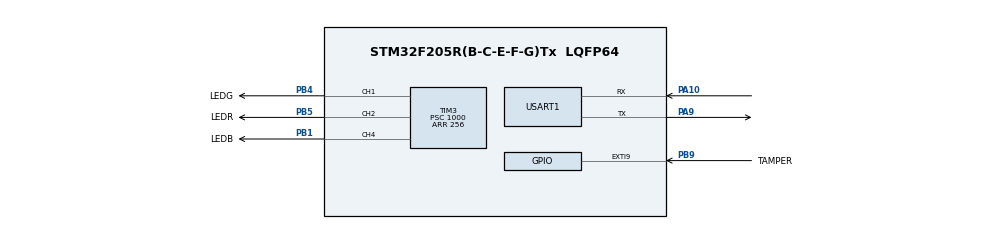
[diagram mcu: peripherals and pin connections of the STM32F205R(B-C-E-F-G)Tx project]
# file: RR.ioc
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Dma.Request0=USART1_RX
Dma.Request1=USART1_TX
Dma.USART1_RX.0.Direction=DMA_PERIPH_TO_MEMORY
Dma.USART1_RX.0.FIFOMode=DMA_FIFOMODE_DISABLE
Dma.USART1_RX.0.Instance=DMA2_Stream2
Dma.USART1_RX.0.MemDataAlignment=DMA_MDATAALIGN_BYTE
Dma.USART1_RX.0.MemInc=DMA_MINC_ENABLE
Dma.USART1_RX.0.Mode=DMA_NORMAL
Dma.USART1_RX.0.PeriphDataAlignment=DMA_PDATAALIGN_BYTE
Dma.USART1_RX.0.PeriphInc=DMA_PINC_DISABLE
Dma.USART1_RX.0.Priority=DMA_PRIORITY_LOW
Dma.USART1_TX.1.Direction=DMA_MEMORY_TO_PERIPH
Dma.USART1_TX.1.FIFOMode=DMA_FIFOMODE_DISABLE
Dma.USART1_TX.1.Instance=DMA2_Stream7
Dma.USART1_TX.1.MemDataAlignment=DMA_MDATAALIGN_BYTE
Dma.USART1_TX.1.MemInc=DMA_MINC_ENABLE
Dma.USART1_TX.1.Mode=DMA_NORMAL
Dma.USART1_TX.1.PeriphDataAlignment=DMA_PDATAALIGN_BYTE
Dma.USART1_TX.1.PeriphInc=DMA_PINC_DISABLE
Dma.USART1_TX.1.Priority=DMA_PRIORITY_LOW
Mcu.Family=STM32F2
Mcu.Name=STM32F205R(B-C-E-F-G)Tx
Mcu.Package=LQFP64
NVIC.DMA2_Stream2_IRQn=true\:0\:0\:false\:false\:true\:false\:true
NVIC.DMA2_Stream7_IRQn=true\:0\:0\:false\:false\:true\:false\:true
NVIC.EXTI9_5_IRQn=true\:0\:0\:false\:false\:true\:true\:true
NVIC.PriorityGroup=NVIC_PRIORITYGROUP_4
NVIC.USART1_IRQn=true\:0\:0\:false\:false\:true\:true\:true
PA10.Mode=Asynchronous
PA10.Signal=USART1_RX
PA9.Mode=Asynchronous
PA9.Signal=USART1_TX
PB1.GPIO_Label=LEDB
PB1.Signal=S_TIM3_CH4
PB4.GPIO_Label=LEDG
PB4.Signal=S_TIM3_CH1
PB5.GPIO_Label=LEDR
PB5.Signal=S_TIM3_CH2
PB9.GPIO_Label=TAMPER
PB9.GPIO_PuPd=GPIO_PULLUP
PB9.Signal=GPXTI9
PH0-OSC_IN.Mode=HSE-External-Oscillator
PH0-OSC_IN.Signal=RCC_OSC_IN
PH1-OSC_OUT.Mode=HSE-External-Oscillator
PH1-OSC_OUT.Signal=RCC_OSC_OUT
ProjectManager.HeapSize=0x200
ProjectManager.StackSize=0x400
ProjectManager.TargetToolchain=Makefile
RCC.48MHZClocksFreq_Value=56000000
RCC.AHBFreq_Value=112000000
RCC.APB1CLKDivider=RCC_HCLK_DIV4
RCC.APB1Freq_Value=28000000
RCC.APB1TimFreq_Value=56000000
RCC.APB2CLKDivider=RCC_HCLK_DIV2
RCC.APB2Freq_Value=56000000
RCC.APB2TimFreq_Value=112000000
RCC.CortexFreq_Value=112000000
RCC.HCLKFreq_Value=112000000
RCC.HSE_VALUE=8000000
RCC.HSI_VALUE=16000000
RCC.LSE_VALUE=32768
RCC.PLLM=8
RCC.PLLN=224
RCC.PLLSourceVirtual=RCC_PLLSOURCE_HSE
RCC.SYSCLKFreq_VALUE=112000000
RCC.SYSCLKSource=RCC_SYSCLKSOURCE_PLLCLK
RCC.VCOOutputFreq_Value=224000000
SH.S_TIM3_CH1.0=TIM3_CH1,PWM Generation1 CH1
SH.S_TIM3_CH2.0=TIM3_CH2,PWM Generation2 CH2
SH.S_TIM3_CH4.0=TIM3_CH4,PWM Generation4 CH4
TIM3.Channel-PWM\ Generation1\ CH1=TIM_CHANNEL_1
TIM3.Channel-PWM\ Generation2\ CH2=TIM_CHANNEL_2
TIM3.Channel-PWM\ Generation4\ CH4=TIM_CHANNEL_4
TIM3.ClockDivision=TIM_CLOCKDIVISION_DIV2
TIM3.Period=256
TIM3.Prescaler=1000
TIM3.Pulse-PWM\ Generation1\ CH1=0
TIM3.Pulse-PWM\ Generation4\ CH4=0
USART1.VirtualMode=VM_ASYNC
VP_TIM3_VS_ClockSourceINT.Mode=Internal
board=custom

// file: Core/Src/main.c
/* USER CODE BEGIN Header */
/**
  ******************************************************************************
  * @file           : main.c
  * @brief          : Main program body
  ******************************************************************************
  * @attention
  *
  * Copyright (c) 2024 STMicroelectronics.
  * All rights reserved.
  *
  * This software is licensed under terms that can be found in the LICENSE file
  * in the root directory of this software component.
  * If no LICENSE file comes with this software, it is provided AS-IS.
  *
  ******************************************************************************
  */
/* USER CODE END Header */
#include "main.h"

/* USER CODE BEGIN Includes */

#include<string.h>
#include<command_line.h>
#include<motor.h>

/* USER CODE END Includes */

TIM_HandleTypeDef htim3;

UART_HandleTypeDef huart1;
DMA_HandleTypeDef hdma_usart1_rx;
DMA_HandleTypeDef hdma_usart1_tx;

void SystemClock_Config(void);
static void MX_GPIO_Init(void);
static void MX_DMA_Init(void);
static void MX_TIM3_Init(void);
static void MX_USART1_UART_Init(void);

/* USER CODE BEGIN 0 */

char *user_data = "The application is running\r\n"; //demo data for transmission-
char *command;
uint8_t data_buffer[100]; // data buffer
uint8_t recvd_data; // receive buffer
uint32_t count=0; // count how many bytes are received
uint8_t command_flag = 0;

/* USER CODE END 0 */

int main(void)
{

  /* MCU Configuration--------------------------------------------------------*/

  /* Reset of all peripherals, Initializes the Flash interface and the Systick. */
  HAL_Init();

  /* Configure the system clock */
  SystemClock_Config();

  /* Initialize all configured peripherals */
  MX_GPIO_Init();
  MX_DMA_Init();
  MX_TIM3_Init();
  MX_USART1_UART_Init();
  /* USER CODE BEGIN 2 */

  			HAL_GPIO_WritePin(GPIOC, GPIO_FL_Pin, GPIO_PIN_RESET);
				HAL_GPIO_WritePin(GPIOC, GPIO_FR_Pin, GPIO_PIN_RESET);
				HAL_GPIO_WritePin(GPIOC, GPIO_BL_Pin, GPIO_PIN_RESET);
				HAL_GPIO_WritePin(GPIOC, GPIO_BR_Pin, GPIO_PIN_RESET);

  HAL_UART_Transmit_IT(&huart1,(uint8_t*)user_data,strlen(user_data)); //Transmit data in interrupt mode
  HAL_UART_Receive_IT(&huart1,&recvd_data,1); //receive data from data buffer interrupt mode

  /* USER CODE END 2 */

  /* Infinite loop */
  while (1)
  {

    /* USER CODE BEGIN 3 */

    if(command_flag){
      Get_Command(data_buffer);
    }

    if (GPIO_PIN_SET == HAL_GPIO_ReadPin(GPIOA, GPIO_PIN_0)) {

		  HAL_GPIO_WritePin(GPIOC, GPIO_PIN_13, GPIO_PIN_SET);

      TIM3 -> CCR1 = 1000;
      TIM3 -> CCR2 = 1000;
      TIM3 -> CCR3 = 1000;
      TIM3 -> CCR4 = 1000;

      HAL_TIM_PWM_Stop(&htim3, TIM_CHANNEL_1);
		  HAL_TIM_PWM_Stop(&htim3, TIM_CHANNEL_2);
		  HAL_TIM_PWM_Stop(&htim3, TIM_CHANNEL_3);
		  HAL_TIM_PWM_Stop(&htim3, TIM_CHANNEL_4);

    } else {

		  HAL_GPIO_WritePin(GPIOC, GPIO_PIN_13, GPIO_PIN_RESET);

		  HAL_Delay(2000);

		  HAL_TIM_PWM_Start(&htim3, TIM_CHANNEL_1);
		  HAL_TIM_PWM_Start(&htim3, TIM_CHANNEL_2);
		  HAL_TIM_PWM_Start(&htim3, TIM_CHANNEL_3);
		  HAL_TIM_PWM_Start(&htim3, TIM_CHANNEL_4);

      /*
		  wheelControl(frontright, 8);
		  HAL_Delay(1000);

		  wheelControl(frontright, 0);
		  HAL_Delay(1000);

		  wheelControl(backright, 8);
		  HAL_Delay(1000);

		  wheelControl(backright, 0);
		  HAL_Delay(1000);

		  wheelControl(frontleft, 8);
		  HAL_Delay(1000);

		  wheelControl(frontleft, 0);
		  HAL_Delay(1000);

		  wheelControl(backleft, 8);
		  HAL_Delay(1000);

		  wheelControl(backleft, 0);
		  HAL_Delay(1000);
*/

		  //wheelControl(backleft, 20);
//	  TIM3 -> CCR1 = 1000;
//	  TIM4 -> CCR1 = 199;

    TIM1 -> CCR2 = 1000;
    TIM2 -> CCR2 = 0;

 //   TIM1 -> CCR3 = 1000;
//    TIM2 -> CCR3 = 199;

//    TIM1 -> CCR4 = 1000;
//    TIM2 -> CCR4 = 199;

	  HAL_Delay(4000);

    }
  }
  /* USER CODE END 3 */
}

void SystemClock_Config(void)
{
  RCC_OscInitTypeDef RCC_OscInitStruct = {0};
  RCC_ClkInitTypeDef RCC_ClkInitStruct = {0};

  /** Configure the main internal regulator output voltage
  */
  __HAL_RCC_PWR_CLK_ENABLE();
  __HAL_PWR_VOLTAGESCALING_CONFIG(PWR_REGULATOR_VOLTAGE_SCALE2);

  /** Initializes the RCC Oscillators according to the specified parameters
  * in the RCC_OscInitTypeDef structure.
  */
  RCC_OscInitStruct.OscillatorType = RCC_OSCILLATORTYPE_HSE;
  RCC_OscInitStruct.HSEState = RCC_HSE_ON;
  RCC_OscInitStruct.PLL.PLLState = RCC_PLL_ON;
  RCC_OscInitStruct.PLL.PLLSource = RCC_PLLSOURCE_HSE;
  RCC_OscInitStruct.PLL.PLLM = 25;
  RCC_OscInitStruct.PLL.PLLN = 168;
  RCC_OscInitStruct.PLL.PLLP = RCC_PLLP_DIV2;
  RCC_OscInitStruct.PLL.PLLQ = 4;
  if (HAL_RCC_OscConfig(&RCC_OscInitStruct) != HAL_OK)
  {
    Error_Handler();
  }

  /** Initializes the CPU, AHB and APB buses clocks
  */
  RCC_ClkInitStruct.ClockType = RCC_CLOCKTYPE_HCLK|RCC_CLOCKTYPE_SYSCLK
                              |RCC_CLOCKTYPE_PCLK1|RCC_CLOCKTYPE_PCLK2;
  RCC_ClkInitStruct.SYSCLKSource = RCC_SYSCLKSOURCE_PLLCLK;
  RCC_ClkInitStruct.AHBCLKDivider = RCC_SYSCLK_DIV1;
  RCC_ClkInitStruct.APB1CLKDivider = RCC_HCLK_DIV2;
  RCC_ClkInitStruct.APB2CLKDivider = RCC_HCLK_DIV1;

  if (HAL_RCC_ClockConfig(&RCC_ClkInitStruct, FLASH_LATENCY_2) != HAL_OK)
  {
    Error_Handler();
  }
}

static void MX_TIM3_Init(void)
{

  TIM_ClockConfigTypeDef sClockSourceConfig = {0};
  TIM_MasterConfigTypeDef sMasterConfig = {0};
  TIM_OC_InitTypeDef sConfigOC = {0};

  htim3.Instance = TIM3;
  htim3.Init.Prescaler = 25-1;
  htim3.Init.CounterMode = TIM_COUNTERMODE_UP;
  htim3.Init.Period = 999;
  htim3.Init.ClockDivision = TIM_CLOCKDIVISION_DIV1;
  htim3.Init.AutoReloadPreload = TIM_AUTORELOAD_PRELOAD_DISABLE;
  if (HAL_TIM_Base_Init(&htim3) != HAL_OK)
  {
    Error_Handler();
  }
  sClockSourceConfig.ClockSource = TIM_CLOCKSOURCE_INTERNAL;
  if (HAL_TIM_ConfigClockSource(&htim3, &sClockSourceConfig) != HAL_OK)
  {
    Error_Handler();
  }
  if (HAL_TIM_PWM_Init(&htim3) != HAL_OK)
  {
    Error_Handler();
  }
  sMasterConfig.MasterOutputTrigger = TIM_TRGO_RESET;
  sMasterConfig.MasterSlaveMode = TIM_MASTERSLAVEMODE_DISABLE;
  if (HAL_TIMEx_MasterConfigSynchronization(&htim3, &sMasterConfig) != HAL_OK)
  {
    Error_Handler();
  }
  sConfigOC.OCMode = TIM_OCMODE_PWM1;
  sConfigOC.Pulse = 999;
  sConfigOC.OCPolarity = TIM_OCPOLARITY_HIGH;
  sConfigOC.OCFastMode = TIM_OCFAST_DISABLE;
  if (HAL_TIM_PWM_ConfigChannel(&htim3, &sConfigOC, TIM_CHANNEL_1) != HAL_OK)
  {
    Error_Handler();
  }
  if (HAL_TIM_PWM_ConfigChannel(&htim3, &sConfigOC, TIM_CHANNEL_2) != HAL_OK)
  {
    Error_Handler();
  }
  if (HAL_TIM_PWM_ConfigChannel(&htim3, &sConfigOC, TIM_CHANNEL_3) != HAL_OK)
  {
    Error_Handler();
  }
  if (HAL_TIM_PWM_ConfigChannel(&htim3, &sConfigOC, TIM_CHANNEL_4) != HAL_OK)
  {
    Error_Handler();
  }
  HAL_TIM_MspPostInit(&htim3);

}

static void MX_USART1_UART_Init(void)
{

  huart1.Instance = USART1;
  huart1.Init.BaudRate = 115200;
  huart1.Init.WordLength = UART_WORDLENGTH_8B;
  huart1.Init.StopBits = UART_STOPBITS_1;
  huart1.Init.Parity = UART_PARITY_NONE;
  huart1.Init.Mode = UART_MODE_TX_RX;
  huart1.Init.HwFlowCtl = UART_HWCONTROL_NONE;
  huart1.Init.OverSampling = UART_OVERSAMPLING_16;
  if (HAL_UART_Init(&huart1) != HAL_OK)
  {
    Error_Handler();
  }

}

static void MX_DMA_Init(void)
{

  /* DMA controller clock enable */
  __HAL_RCC_DMA2_CLK_ENABLE();

  /* DMA interrupt init */
  /* DMA2_Stream2_IRQn interrupt configuration */
  HAL_NVIC_SetPriority(DMA2_Stream2_IRQn, 0, 0);
  HAL_NVIC_EnableIRQ(DMA2_Stream2_IRQn);
  /* DMA2_Stream7_IRQn interrupt configuration */
  HAL_NVIC_SetPriority(DMA2_Stream7_IRQn, 0, 0);
  HAL_NVIC_EnableIRQ(DMA2_Stream7_IRQn);

}

static void MX_GPIO_Init(void)
{
  GPIO_InitTypeDef GPIO_InitStruct = {0};

  /* GPIO Ports Clock Enable */
  __HAL_RCC_GPIOC_CLK_ENABLE();
  __HAL_RCC_GPIOH_CLK_ENABLE();
  __HAL_RCC_GPIOA_CLK_ENABLE();
  __HAL_RCC_GPIOB_CLK_ENABLE();

  /*Configure GPIO pin Output Level */
  HAL_GPIO_WritePin(GPIOC, GPIO_PIN_13, GPIO_PIN_RESET);

  /*Configure GPIO pin Output Level */
  HAL_GPIO_WritePin(GPIOB, GPIO_FL_Pin|GPIO_FR_Pin|GPIO_BL_Pin|GPIO_BR_Pin, GPIO_PIN_RESET);

  /*Configure GPIO pin : PC13 */
  GPIO_InitStruct.Pin = GPIO_PIN_13;
  GPIO_InitStruct.Mode = GPIO_MODE_OUTPUT_PP;
  GPIO_InitStruct.Pull = GPIO_NOPULL;
  GPIO_InitStruct.Speed = GPIO_SPEED_FREQ_LOW;
  HAL_GPIO_Init(GPIOC, &GPIO_InitStruct);

  /*Configure GPIO pin : PA0 */
  GPIO_InitStruct.Pin = GPIO_PIN_0;
  GPIO_InitStruct.Mode = GPIO_MODE_INPUT;
  GPIO_InitStruct.Pull = GPIO_NOPULL;
  HAL_GPIO_Init(GPIOA, &GPIO_InitStruct);

  /*Configure GPIO pins : GPIO_FL_Pin GPIO_FR_Pin GPIO_BL_Pin GPIO_BR_Pin */
  GPIO_InitStruct.Pin = GPIO_FL_Pin|GPIO_FR_Pin|GPIO_BL_Pin|GPIO_BR_Pin;
  GPIO_InitStruct.Mode = GPIO_MODE_OUTPUT_PP;
  GPIO_InitStruct.Pull = GPIO_NOPULL;
  GPIO_InitStruct.Speed = GPIO_SPEED_FREQ_VERY_HIGH;
  HAL_GPIO_Init(GPIOB, &GPIO_InitStruct);

}

/* USER CODE BEGIN 4 */

//UART 2 transmission complete callback
void HAL_UART_TxCpltCallback(UART_HandleTypeDef *huart)
{
	memset(user_data, 0, strlen(user_data)); //empty the transmission data buffer

}

//UART 2 receive complete callback
void HAL_UART_RxCpltCallback(UART_HandleTypeDef *huart)
{
	 char *mv_to_next_line = "\r\n";

	 if(recvd_data == '\r') //when enter is pressed go to this condition
	 {

     command_flag = 1;

     HAL_UART_Transmit(&huart1,(uint8_t*)mv_to_next_line,strlen(mv_to_next_line),100);
     memset(mv_to_next_line, 0, strlen(mv_to_next_line));

	 }
	 else
	 {
		 data_buffer[count++] = recvd_data; // every time when interrput is happen, received 1 byte of data
     HAL_UART_Transmit(&huart1,&recvd_data,1,100);
	 }
	 HAL_UART_Receive_IT(&huart1,&recvd_data,1); //start next data receive interrupt
}

/* USER CODE END 4 */

void Error_Handler(void)
{
  __disable_irq();
  while (1)
  {
  }
}
